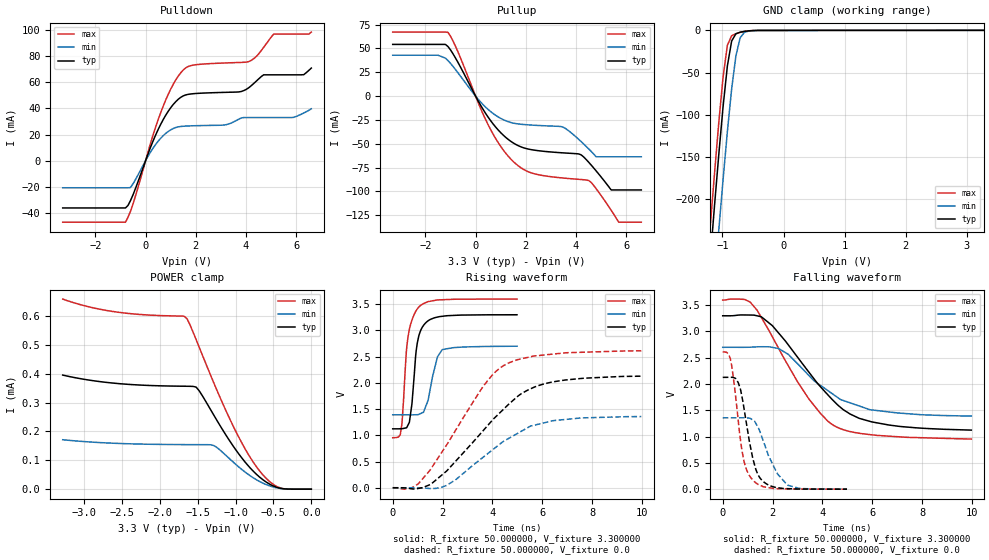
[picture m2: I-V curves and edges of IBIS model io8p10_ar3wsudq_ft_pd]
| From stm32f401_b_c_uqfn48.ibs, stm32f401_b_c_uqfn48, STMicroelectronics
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|   Model io8p10_ar3wsudq_ft_pd
[Model]  io8p10_ar3wsudq_ft_pd
Model_type I/O
Polarity   Non-Inverting
Enable   Active-Low
Vinl =   0.990000V
Vinh =   2.310000V
Vmeas =  1.650000V
Cref =   40.000000pF
Rref =   100.000000M
Vref =   0.0V
C_comp   3.843100pF   3.761700pF   3.937000pF
[Temperature Range]   25.000000   0.125000k   -40.000000
[Pullup Reference]   3.300000V   2.700000V   3.600000V
[Pulldown Reference]   0.0V   0.0V   0.0V
[POWER Clamp Reference]   3.300000V   2.700000V   3.600000V
[GND Clamp Reference]   0.0V   0.0V   0.0V
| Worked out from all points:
|   slope of the pulldown table from 0 to 0.495 V, typ, clamps not added: 20.9 ohm
|   slope of the pullup table from 0 to 0.495 V, typ, clamps not added: 22.6 ohm
|   GND clamp passes 1 mA (typ) near -0.62 V on its own axis
|   rising waveform, R_fixture 50.000000, V_fixture 3.300000: 20-80 % time 273ps typ, 357ps min, 284ps max; typ from 1.12 V to 3.3 V
|   rising waveform, R_fixture 50.000000, V_fixture 0.0: 20-80 % time 2.54ns typ, 2.37ns min, 2.13ns max; typ from 0 V to 2.13 V
|   falling waveform, R_fixture 50.000000, V_fixture 3.300000: 20-80 % time 2.29ns typ, 2.15ns min, 2.06ns max; typ from 3.3 V to 1.12 V
|   falling waveform, R_fixture 50.000000, V_fixture 0.0: 20-80 % time 504ps typ, 735ps min, 424ps max; typ from 2.13 V to 0 V
[Pulldown]
|Voltage   I(typ)   I(min)   I(max)
-3.3V     -36.18mA   -20.77mA   -47.07mA
-800mV    -36.18mA   -20.77mA   -47.07mA
-600mV    -30.5mA    -20.52mA   -38.69mA
700mV     31.4mA     19.11mA    41.71mA
1.2V      45.15mA    25.37mA    61.75mA
1.6V      50.35mA    26.5mA     71.06mA
3.1V      52.27mA    27.26mA    74.75mA
4.1V      55.7mA     33.01mA    75.8mA
4.7V      65.73mA    33.01mA    86.69mA
5.1V      65.73mA    33.01mA    96.89mA
6.3V      65.85mA    36.49mA    96.89mA
6.6V      70.9mA     39.7mA     98.44mA
[Pullup]
|Voltage   I(typ)   I(min)   I(max)
-3.3V     54.22mA    42.91mA    67.15mA
-1.1V     51.98mA    37.3mA     66.87mA
500mV     -22.07mA   -14mA      -30.03mA
1.5V      -49.1mA    -28.3mA    -68.56mA
2.2V      -56.04mA   -30.32mA   -80.35mA
3.5V      -59.53mA   -32.72mA   -85.92mA
4.2V      -61.52mA   -47.62mA   -87.46mA
4.5V      -69.21mA   -55.27mA   -88.44mA
4.8V      -78.37mA   -63.6mA    -97.02mA
5.4V      -98.4mA    -63.6mA    -119.7mA
5.7V      -98.4mA    -63.6mA    -132.2mA
6.6V      -98.4mA    -63.6mA    -132.2mA
[GND_clamp]
|Voltage   I(typ)   I(min)   I(max)
-3.3V     -2.325A    -2.404A    -2.299A
-1.2V     -270.2mA   -361.4mA   -232.1mA
-1.13V    -207.3mA   -298.1mA   -169mA
-1.06V    -146.7mA   -236.2mA   -108.8mA
-990mV    -90.18mA   -176.4mA   -54.97mA
-920mV    -42.21mA   -120mA     -17.69mA
-850mV    -12.58mA   -69.47mA   -6.279mA
-780mV    -3.983mA   -30.01mA   -3.9mA
-710mV    -2.112mA   -8.623mA   -2.396mA
-640mV    -1.159mA   -2.292mA   -1.234mA
-570mV    -535.1uA   -830.5uA   -490.2uA
3.28V     81.28uA    57.87uA    93.98uA
[POWER_clamp]
|Voltage   I(typ)   I(min)   I(max)
-3.28V    395.3uA    171.3uA    658.7uA
-2.6V     367.1uA    159uA      614.9uA
-1.68V    356.7uA    154.4uA    599.4uA
-1.64V    356.5uA    154.4uA    590.8uA
-1.52V    353.6uA    154.3uA    518.3uA
-1.48V    341.1uA    154.2uA    492.3uA
-1.28V    253.6uA    150.4uA    364.2uA
-960mV    123.1uA    77.56uA    181.6uA
-720mV    50.52uA    32.03uA    76.18uA
-560mV    18.94uA    12.27uA    28.65uA
-440mV    5.104uA    3.69uA     7.327uA
0V        0A         0A         0A
[Ramp]
| variable   typ   min   max
dV/dt_r  1.26618/2.54219n   0.81048/2.36713n   1.56348/2.13137n
dV/dt_f  1.28238/2.27117n   0.77610/2.13563n   1.57432/2.05496n
R_load = 50.000000
[Rising Waveform]
R_fixture= 50.000000
V_fixture= 3.300000
V_fixture_min= 2.700000
V_fixture_max= 3.600000
|time   V(typ)   V(min)   V(max)
0s        1.123V     1.391V     953.9mV
300.3ps   1.125V     1.391V     1.006V
370.4ps   1.126V     1.391V     1.218V
550.6ps   1.143V     1.391V     2.615V
670.7ps   1.254V     1.39V      3.025V
1.031ns   2.861V     1.396V     3.438V
1.411ns   3.181V     1.658V     3.547V
1.792ns   3.254V     2.491V     3.581V
1.982ns   3.269V     2.631V     3.585V
4.985ns   3.299V     2.699V     3.598V
[Rising Waveform]
R_fixture= 50.000000
V_fixture= 0.0
V_fixture_min= 0.0
V_fixture_max= 0.0
|time   V(typ)   V(min)   V(max)
0s        344.2uV    196.7uV    676.9uV
480.5ps   -2.556mV   137.5uV    -26.14mV
1.021ns   -13.38mV   -1.475mV   72.37mV
1.522ns   64.62mV    -15.8mV    352.4mV
2.142ns   310.8mV    41.11mV    803mV
3.644ns   1.098V     588.6mV    1.941V
4.484ns   1.516V     896.8mV    2.339V
5.165ns   1.796V     1.079V     2.459V
6.246ns   2V         1.258V     2.54V
9.97ns    2.127V     1.357V     2.611V
[Falling Waveform]
R_fixture= 50.000000
V_fixture= 3.300000
V_fixture_min= 2.700000
V_fixture_max= 3.600000
|time   V(typ)   V(min)   V(max)
0s        3.299V     2.699V     3.598V
1.101ns   3.312V     2.701V     3.559V
1.542ns   3.281V     2.709V     3.273V
2.242ns   2.97V      2.676V     2.678V
2.643ns   2.737V     2.559V     2.337V
3.463ns   2.222V     2.16V      1.71V
4.484ns   1.662V     1.786V     1.203V
5.105ns   1.431V     1.643V     1.096V
5.986ns   1.279V     1.507V     1.034V
9.97ns    1.123V     1.391V     953.9mV
[Falling Waveform]
R_fixture= 50.000000
V_fixture= 0.0
V_fixture_min= 0.0
V_fixture_max= 0.0
|time   V(typ)   V(min)   V(max)
0s        2.127V     1.357V     2.611V
300.3ps   2.128V     1.357V     2.49V
470.5ps   2.116V     1.357V     1.962V
620.6ps   2.029V     1.357V     1.317V
850.9ps   1.546V     1.359V     537.6mV
1.201ns   597.4mV    1.316V     177mV
1.622ns   147.8mV    925.3mV    48.44mV
2.192ns   28.84mV    293.7mV    9.852mV
2.593ns   10.2mV     79mV       5.363mV
4.985ns   344.2uV    196.7uV    676.9uV
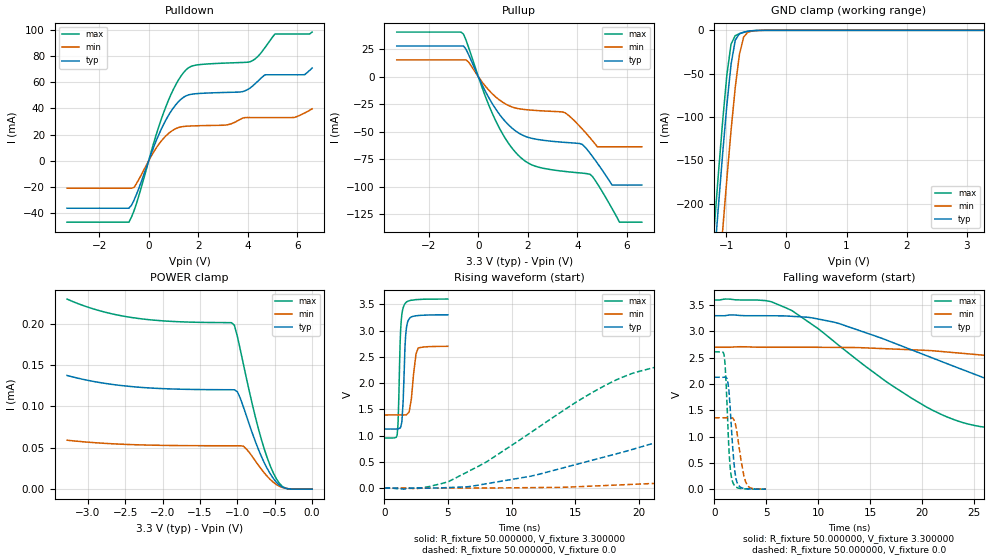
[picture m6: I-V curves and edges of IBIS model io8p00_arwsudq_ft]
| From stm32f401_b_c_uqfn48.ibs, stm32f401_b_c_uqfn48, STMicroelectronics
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|   Model io8p00_arwsudq_ft
[Model]  io8p00_arwsudq_ft
Model_type I/O
Polarity   Non-Inverting
Enable   Active-Low
Vinl =   0.990000V
Vinh =   2.310000V
Vmeas =  1.650000V
Cref =   50.000000pF
Rref =   100.000000M
Vref =   0.0V
C_comp   2.905500pF   2.831700pF   2.987900pF
[Temperature Range]   25.000000   0.125000k   -40.000000
[Pullup Reference]   3.300000V   2.700000V   3.600000V
[Pulldown Reference]   0.0V   0.0V   0.0V
[POWER Clamp Reference]   3.300000V   2.700000V   3.600000V
[GND Clamp Reference]   0.0V   0.0V   0.0V
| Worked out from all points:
|   slope of the pulldown table from 0 to 0.495 V, typ, clamps not added: 20.9 ohm
|   slope of the pullup table from 0 to 0.495 V, typ, clamps not added: 22.6 ohm
|   GND clamp passes 1 mA (typ) near -0.62 V on its own axis
|   rising waveform, R_fixture 50.000000, V_fixture 3.300000: 20-80 % time 211ps typ, 337ps min, 189ps max; typ from 1.12 V to 3.3 V
|   rising waveform, R_fixture 50.000000, V_fixture 0.0: 20-80 % time 19.7ns typ, 50.8ns min, 10.3ns max; typ from 0 V to 2.13 V
|   falling waveform, R_fixture 50.000000, V_fixture 3.300000: 20-80 % time 18.4ns typ, 38.3ns min, 11.3ns max; typ from 3.3 V to 1.12 V
|   falling waveform, R_fixture 50.000000, V_fixture 0.0: 20-80 % time 461ps typ, 654ps min, 370ps max; typ from 2.13 V to 0 V
[Pulldown]
|Voltage   I(typ)   I(min)   I(max)
-3.3V     -36.4mA    -21.08mA   -47.09mA
-800mV    -36.4mA    -21.08mA   -47.09mA
-600mV    -30.5mA    -20.54mA   -38.69mA
700mV     31.4mA     19.11mA    41.71mA
1.2V      45.15mA    25.37mA    61.75mA
1.6V      50.35mA    26.5mA     71.06mA
3.1V      52.28mA    27.26mA    74.76mA
4.1V      55.71mA    33.04mA    75.8mA
4.7V      65.81mA    33.04mA    86.69mA
5.1V      65.81mA    33.04mA    97.04mA
6.3V      65.87mA    36.5mA     97.04mA
6.6V      70.93mA    39.72mA    98.49mA
[Pullup]
|Voltage   I(typ)   I(min)   I(max)
-3.3V     28.03mA    15.43mA    40.68mA
-700mV    28.03mA    15.43mA    40.68mA
-400mV    20.31mA    13.47mA    26.93mA
600mV     -25.77mA   -16.23mA   -35.13mA
1.6V      -50.64mA   -28.81mA   -70.96mA
3.5V      -59.53mA   -32.65mA   -85.92mA
4.2V      -61.44mA   -47.49mA   -87.46mA
4.5V      -69.08mA   -55.13mA   -88.39mA
4.8V      -78.24mA   -63.5mA    -96.88mA
5.4V      -98.3mA    -63.5mA    -119.6mA
5.7V      -98.3mA    -63.5mA    -132mA
6.6V      -98.3mA    -63.5mA    -132mA
[GND_clamp]
|Voltage   I(typ)   I(min)   I(max)
-3.3V     -2.32A     -2.398A    -2.294A
-1.2V     -266mA     -356.2mA   -228.4mA
-1.13V    -203.2mA   -293mA     -165.3mA
-1.06V    -142.7mA   -231.3mA   -105.2mA
-990mV    -86.51mA   -171.7mA   -51.78mA
-920mV    -39.3mA    -115.7mA   -15.93mA
-850mV    -11.37mA   -65.76mA   -6.097mA
-780mV    -3.83mA    -27.55mA   -3.88mA
-710mV    -2.09mA    -7.747mA   -2.382mA
-640mV    -1.147mA   -2.129mA   -1.22mA
-570mV    -523.9uA   -800uA     -476.9uA
3.28V     0A         0A         0A
[POWER_clamp]
|Voltage   I(typ)   I(min)   I(max)
-3.28V    137.3uA    59.14uA    229.6uA
-2.36V    123.4uA    53.65uA    206.6uA
-1.08V    120.1uA    52.41uA    201.1uA
-1.04V    120uA      52.41uA    198uA
-1V       117.7uA    52.4uA     184.5uA
-920mV    99.46uA    51.91uA    151.2uA
-720mV    48.42uA    29.12uA    73.51uA
-600mV    24.82uA    15.47uA    37.72uA
-520mV    13.1uA     8.45uA     19.84uA
-440mV    5.058uA    3.61uA     7.276uA
-360mV    1.193uA    1.129uA    1.311uA
0V        0A         0A         0A
[Ramp]
| variable   typ   min   max
dV/dt_r  1.27746/19.70668n   0.81594/50.89464n   1.56731/10.31914n
dV/dt_f  1.30698/18.44695n   0.78480/38.43512n   1.58789/11.32160n
R_load = 50.000000
[Rising Waveform]
R_fixture= 50.000000
V_fixture= 3.300000
V_fixture_min= 2.700000
V_fixture_max= 3.600000
|time   V(typ)   V(min)   V(max)
0s        1.124V     1.392V     953.5mV
1.001ns   1.126V     1.392V     1.012V
1.071ns   1.127V     1.392V     1.26V
1.271ns   1.159V     1.392V     3.005V
1.371ns   1.27V      1.391V     3.312V
1.532ns   2.086V     1.392V     3.475V
1.672ns   2.92V      1.394V     3.53V
1.932ns   3.219V     1.445V     3.567V
2.653ns   3.286V     2.667V     3.591V
4.985ns   3.3V       2.7V       3.6V
[Rising Waveform]
R_fixture= 50.000000
V_fixture= 0.0
V_fixture_min= 0.0
V_fixture_max= 0.0
|time   V(typ)   V(min)   V(max)
0s        1.506uV    364.5nV    16.56uV
5.005ns   8.627mV    -160uV     117.5mV
19.52ns   735.6mV    69.76mV    2.185V
26.03ns   1.193V     138.3mV    2.462V
34.03ns   1.683V     279.6mV    2.558V
41.04ns   1.911V     403.2mV    2.582V
57.06ns   2.066V     700.6mV    2.607V
88.09ns   2.119V     1.131V     2.612V
115.1ns   2.128V     1.292V     2.612V
249.2ns   2.129V     1.359V     2.612V
[Falling Waveform]
R_fixture= 50.000000
V_fixture= 3.300000
V_fixture_min= 2.700000
V_fixture_max= 3.600000
|time   V(typ)   V(min)   V(max)
0s        3.3V       2.7V       3.6V
5.506ns   3.299V     2.7V       3.565V
11.51ns   3.178V     2.697V     2.814V
17.02ns   2.803V     2.668V     1.984V
22.02ns   2.418V     2.616V     1.407V
31.53ns   1.726V     2.437V     1.075V
46.05ns   1.281V     2.083V     999.4mV
65.07ns   1.179V     1.708V     968mV
86.59ns   1.146V     1.527V     956.5mV
249.2ns   1.124V     1.392V     953.5mV
[Falling Waveform]
R_fixture= 50.000000
V_fixture= 0.0
V_fixture_min= 0.0
V_fixture_max= 0.0
|time   V(typ)   V(min)   V(max)
0s        2.129V     1.359V     2.612V
981ps     2.13V      1.359V     2.514V
1.151ns   2.121V     1.358V     1.992V
1.311ns   2.034V     1.358V     1.244V
1.491ns   1.679V     1.36V      532mV
1.792ns   768.6mV    1.352V     130.2mV
2.182ns   139.1mV    1.095V     32.63mV
2.843ns   15.25mV    270mV      6.343mV
3.143ns   7.383mV    88.48mV    4.542mV
4.985ns   1.506uV    364.5nV    16.56uV
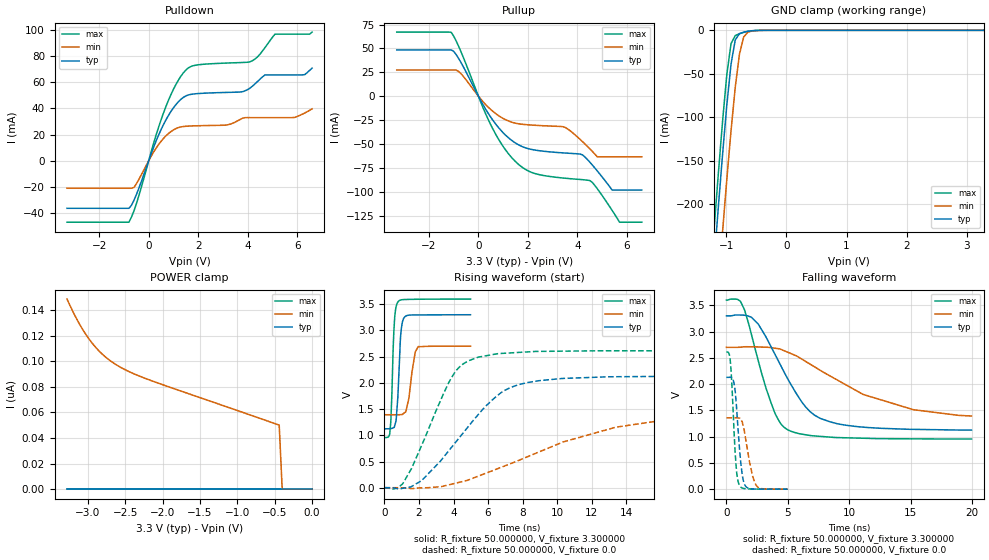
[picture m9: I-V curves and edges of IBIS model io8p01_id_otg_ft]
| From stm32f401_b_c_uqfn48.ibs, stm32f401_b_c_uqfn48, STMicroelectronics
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|   Model io8p01_id_otg_ft
[Model]  io8p01_id_otg_ft
Model_type I/O
Polarity   Non-Inverting
Enable   Active-Low
Vinl =   0.990000V
Vinh =   2.310000V
Vmeas =  1.650000V
Cref =   50.000000pF
Rref =   100.000000M
Vref =   0.0V
C_comp   2.283100pF   2.214500pF   2.357400pF
[Temperature Range]   25.000000   0.125000k   -40.000000
[Pullup Reference]   3.300000V   2.700000V   3.600000V
[Pulldown Reference]   0.0V   0.0V   0.0V
[POWER Clamp Reference]   3.300000V   2.700000V   3.600000V
[GND Clamp Reference]   0.0V   0.0V   0.0V
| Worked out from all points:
|   slope of the pulldown table from 0 to 0.495 V, typ, clamps not added: 20.9 ohm
|   slope of the pullup table from 0 to 0.495 V, typ, clamps not added: 22.6 ohm
|   GND clamp passes 1 mA (typ) near -0.62 V on its own axis
|   rising waveform, R_fixture 50.000000, V_fixture 3.300000: 20-80 % time 192ps typ, 331ps min, 165ps max; typ from 1.12 V to 3.3 V
|   rising waveform, R_fixture 50.000000, V_fixture 0.0: 20-80 % time 3.34ns typ, 6.83ns min, 2.09ns max; typ from 0 V to 2.13 V
|   falling waveform, R_fixture 50.000000, V_fixture 3.300000: 20-80 % time 3.18ns typ, 6.84ns min, 1.99ns max; typ from 3.3 V to 1.12 V
|   falling waveform, R_fixture 50.000000, V_fixture 0.0: 20-80 % time 434ps typ, 634ps min, 342ps max; typ from 2.13 V to 0 V
[Pulldown]
|Voltage   I(typ)   I(min)   I(max)
-3.3V     -36.46mA   -21.09mA   -47.09mA
-800mV    -36.46mA   -21.09mA   -47.09mA
-600mV    -30.5mA    -20.54mA   -38.68mA
700mV     31.4mA     19.11mA    41.71mA
1.2V      45.15mA    25.37mA    61.75mA
1.6V      50.35mA    26.5mA     71.06mA
3.1V      52.28mA    27.26mA    74.76mA
4.1V      55.71mA    33mA       75.81mA
4.7V      65.72mA    33mA       86.7mA
5.1V      65.72mA    33mA       96.91mA
6.3V      65.88mA    36.51mA    96.91mA
6.6V      70.94mA    39.72mA    98.51mA
[Pullup]
|Voltage   I(typ)   I(min)   I(max)
-3.3V     48.55mA    27.44mA    67.19mA
-1.1V     48.55mA    27.44mA    66.9mA
-700mV    35.14mA    23.48mA    46.36mA
500mV     -22.07mA   -14mA      -30.03mA
1.5V      -49.1mA    -28.3mA    -68.56mA
2.2V      -56.05mA   -30.32mA   -80.35mA
3.5V      -59.53mA   -32.65mA   -85.92mA
4.5V      -69.06mA   -55.12mA   -88.38mA
4.8V      -78.22mA   -63.5mA    -96.84mA
5.4V      -98.3mA    -63.5mA    -119.6mA
5.7V      -98.3mA    -63.5mA    -132mA
6.6V      -98.3mA    -63.5mA    -132mA
[GND_clamp]
|Voltage   I(typ)   I(min)   I(max)
-3.3V     -2.318A    -2.397A    -2.291A
-1.2V     -265.5mA   -356.1mA   -227.2mA
-1.13V    -202.7mA   -292.9mA   -164.1mA
-1.06V    -142.2mA   -231.2mA   -104.1mA
-990mV    -85.98mA   -171.6mA   -50.73mA
-920mV    -38.81mA   -115.5mA   -15.3mA
-850mV    -11.1mA    -65.61mA   -6.021mA
-780mV    -3.796mA   -27.43mA   -3.892mA
-710mV    -2.096mA   -7.699mA   -2.393mA
-640mV    -1.154mA   -2.125mA   -1.227mA
-570mV    -528.1uA   -803.6uA   -480.7uA
3.28V     0A         0A         0A
[POWER_clamp]
|Voltage   I(typ)   I(min)   I(max)
-3.28V    0A         148.5nA    0A
-3.2V     0A         138.6nA    0A
-3.12V    0A         129.7nA    0A
-3.04V    0A         122nA      0A
-2.96V    0A         115.3nA    0A
-2.8V     0A         105.1nA    0A
-2.6V     0A         96.44nA    0A
-2.4V     0A         90.52nA    0A
-2.16V    0A         84.97nA    0A
-440mV    0A         50.04nA    0A
-400mV    0A         0A         0A
0V        0A         0A         0A
[Ramp]
| variable   typ   min   max
dV/dt_r  1.27758/3.33724n   0.79926/6.83450n   1.56726/2.08840n
dV/dt_f  1.30236/3.17443n   0.74064/6.80123n   1.58786/1.98906n
R_load = 50.000000
[Rising Waveform]
R_fixture= 50.000000
V_fixture= 3.300000
V_fixture_min= 2.700000
V_fixture_max= 3.600000
|time   V(typ)   V(min)   V(max)
0s        1.124V     1.392V     954.3mV
300.3ps   1.126V     1.392V     1.015V
370.4ps   1.128V     1.392V     1.28V
500.5ps   1.142V     1.392V     2.635V
590.6ps   1.182V     1.392V     3.246V
760.8ps   1.665V     1.391V     3.534V
940.9ps   2.917V     1.394V     3.582V
1.161ns   3.255V     1.431V     3.59V
1.952ns   3.296V     2.691V     3.595V
4.985ns   3.3V       2.7V       3.599V
[Rising Waveform]
R_fixture= 50.000000
V_fixture= 0.0
V_fixture_min= 0.0
V_fixture_max= 0.0
|time   V(typ)   V(min)   V(max)
0s        358.2uV    205.3uV    684.7uV
1.081ns   -9.554mV   -1.989mV   89.21mV
2.162ns   138.2mV    -2.126mV   814.9mV
3.724ns   704.7mV    54.71mV    2.005V
4.244ns   917.5mV    95.9mV     2.269V
4.885ns   1.178V     150.7mV    2.423V
6.767ns   1.817V     390.3mV    2.562V
8.248ns   2.003V     586mV      2.59V
13.41ns   2.117V     1.155V     2.612V
19.94ns   2.129V     1.359V     2.612V
[Falling Waveform]
R_fixture= 50.000000
V_fixture= 3.300000
V_fixture_min= 2.700000
V_fixture_max= 3.600000
|time   V(typ)   V(min)   V(max)
0s        3.3V       2.7V       3.599V
920.9ps   3.315V     2.7V       3.611V
1.441ns   3.311V     2.71V      3.43V
2.563ns   3.149V     2.707V     2.469V
3.644ns   2.705V     2.693V     1.635V
4.965ns   2.11V      2.609V     1.134V
6.807ns   1.475V     2.38V      1.022V
8.408ns   1.284V     2.158V     991.3mV
15.22ns   1.139V     1.513V     958.1mV
19.94ns   1.124V     1.392V     954.3mV
[Falling Waveform]
R_fixture= 50.000000
V_fixture= 0.0
V_fixture_min= 0.0
V_fixture_max= 0.0
|time   V(typ)   V(min)   V(max)
0s        2.129V     1.359V     2.612V
300.3ps   2.13V      1.359V     2.474V
460.5ps   2.118V     1.358V     1.91V
620.6ps   2.016V     1.358V     1.086V
830.8ps   1.524V     1.36V      324.7mV
1.041ns   833.4mV    1.353V     83.01mV
1.451ns   103.7mV    1.118V     11.68mV
1.872ns   12.72mV    525.3mV    4.407mV
2.422ns   2.904mV    73.74mV    2.293mV
4.985ns   358.2uV    205.3uV    684.7uV
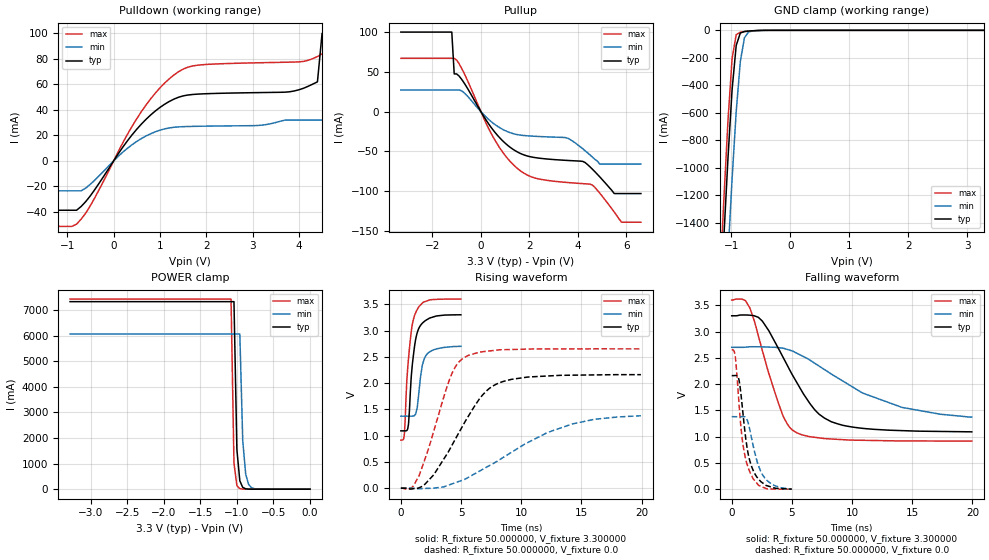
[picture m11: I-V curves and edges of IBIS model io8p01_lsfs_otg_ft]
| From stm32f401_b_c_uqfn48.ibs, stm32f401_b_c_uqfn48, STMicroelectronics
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|   Model io8p01_lsfs_otg_ft
[Model]  io8p01_lsfs_otg_ft
Model_type I/O
Polarity   Non-Inverting
Enable   Active-Low
Vinl =   0.990000V
Vinh =   2.310000V
Vmeas =  1.650000V
Cref =   50.000000pF
Rref =   100.000000M
Vref =   0.0V
C_comp   8.196500pF   7.968500pF   8.492600pF
[Temperature Range]   25.000000   0.125000k   -40.000000
[Pullup Reference]   3.300000V   2.700000V   3.600000V
[Pulldown Reference]   0.0V   0.0V   0.0V
[POWER Clamp Reference]   3.300000V   2.700000V   3.600000V
[GND Clamp Reference]   0.0V   0.0V   0.0V
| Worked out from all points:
|   slope of the pulldown table from 0 to 0.495 V, typ, clamps not added: 20.1 ohm
|   slope of the pullup table from 0 to 0.495 V, typ, clamps not added: 21.8 ohm
|   GND clamp passes 1 mA (typ) near -0.52 V on its own axis
|   POWER clamp passes 1 mA (typ) near -0.81 V on its own axis
|   rising waveform, R_fixture 50.000000, V_fixture 3.300000: 20-80 % time 528ps typ, 494ps min, 531ps max; typ from 1.09 V to 3.3 V
|   rising waveform, R_fixture 50.000000, V_fixture 0.0: 20-80 % time 3.4ns typ, 6.58ns min, 2.17ns max; typ from 0 V to 2.16 V
|   falling waveform, R_fixture 50.000000, V_fixture 3.300000: 20-80 % time 3.37ns typ, 6.54ns min, 2.12ns max; typ from 3.3 V to 1.09 V
|   falling waveform, R_fixture 50.000000, V_fixture 0.0: 20-80 % time 848ps typ, 1.03ns min, 757ps max; typ from 2.16 V to 0 V
[Pulldown]
|Voltage   I(typ)   I(min)   I(max)
-3.3V     -38.65mA   -23.43mA   -51.3mA
-800mV    -38.65mA   -23.43mA   -49.55mA
600mV     28.89mA    17.56mA    38.66mA
1.4V      49.88mA    26.66mA    69.85mA
4.1V      56.96mA    32mA       77.99mA
4.4V      62mA       32mA       81.81mA
4.5V      100mA      32mA       83.91mA
4.7V      100mA      32mA       89mA
4.8V      100mA      32mA       100mA
5.1V      100mA      32mA       100mA
5.2V      1A         1A         100mA
6.6V      1A         1A         1A
[Pullup]
|Voltage   I(typ)   I(min)   I(max)
-3.3V     100mA      27.2mA     67mA
-1.2V     100mA      27.2mA     67mA
-1.1V     47.4mA     27.2mA     67mA
-700mV    36.47mA    23.93mA    48.81mA
500mV     -22.94mA   -14.36mA   -31.63mA
1.3V      -46.85mA   -27.39mA   -65.63mA
2.1V      -57.1mA    -30.77mA   -82.2mA
3.5V      -61.24mA   -32.7mA    -88.93mA
4.6V      -72.4mA    -57.1mA    -92.27mA
5.5V      -103mA     -66mA      -126.3mA
5.8V      -103mA     -66mA      -139mA
6.6V      -103mA     -66mA      -139mA
[GND_clamp]
|Voltage   I(typ)   I(min)   I(max)
-3.3V     -9.479A    -9.465A    -9.974A
-1.2V     -2.125A    -2.854A    -1.857A
-1.13V    -1.511A    -2.236A    -1.236A
-1.06V    -933.3mA   -1.641A    -660.9mA
-990mV    -433.3mA   -1.082A    -206.9mA
-920mV    -110.3mA   -591mA     -31.45mA
-850mV    -19.78mA   -226.7mA   -13.65mA
-780mV    -8.311mA   -53.93mA   -9.506mA
-710mV    -5.285mA   -11.94mA   -6.262mA
-640mV    -3.232mA   -4.282mA   -3.577mA
3.28V     0A         0A         0A
[POWER_clamp]
|Voltage   I(typ)   I(min)   I(max)
-3.28V    7.328A     6.064A     7.43A
-1.08V    7.328A     6.064A     7.43A
-1.04V    7.328A     6.064A     1.015A
-1V       1.545A     6.064A     138.6mA
-960mV    325.6mA    6.064A     18.93mA
-920mV    68.64mA    1.89A      2.585mA
-880mV    14.47mA    589mA      353uA
-840mV    3.05mA     183.6mA    105.2uA
-800mV    642.9uA    57.21mA    105.2uA
-720mV    28.59uA    5.557mA    105.2uA
0V        0A         0A         0A
[Ramp]
| variable   typ   min   max
dV/dt_r  1.29659/3.39767n   0.80808/6.55318n   1.59073/2.17075n
dV/dt_f  1.32168/3.36534n   0.74892/6.48776n   1.61143/2.12165n
R_load = 50.000000
[Rising Waveform]
R_fixture= 50.000000
V_fixture= 3.300000
V_fixture_min= 2.700000
V_fixture_max= 3.600000
|time   V(typ)   V(min)   V(max)
0s        1.091V     1.371V     914.3mV
290.3ps   1.091V     1.371V     1.025V
500.5ps   1.099V     1.371V     2.067V
630.6ps   1.212V     1.37V      2.457V
870.9ps   2.145V     1.37V      2.993V
1.191ns   2.782V     1.401V     3.318V
1.361ns   2.961V     1.536V     3.4V
1.782ns   3.139V     2.337V     3.522V
2.082ns   3.196V     2.523V     3.558V
4.985ns   3.3V       2.7V       3.6V
[Rising Waveform]
R_fixture= 50.000000
V_fixture= 0.0
V_fixture_min= 0.0
V_fixture_max= 0.0
|time   V(typ)   V(min)   V(max)
0s        34.46uV    22.65uV    108.4uV
800.8ps   -16.48mV   73.79uV    -1.256mV
1.522ns   8.561mV    -12.54mV   241.4mV
2.723ns   252.5mV    385.3uV    1.079V
4.204ns   799.8mV    77.68mV    2.16V
5.526ns   1.339V     196.5mV    2.52V
7.287ns   1.887V     421mV      2.61V
9.169ns   2.071V     679.8mV    2.639V
14.25ns   2.151V     1.223V     2.651V
19.94ns   2.161V     1.379V     2.652V
[Falling Waveform]
R_fixture= 50.000000
V_fixture= 3.300000
V_fixture_min= 2.700000
V_fixture_max= 3.600000
|time   V(typ)   V(min)   V(max)
0s        3.3V       2.7V       3.6V
880.9ps   3.315V     2.7V       3.615V
1.481ns   3.311V     2.71V      3.46V
2.563ns   3.193V     2.708V     2.625V
4.204ns   2.538V     2.685V     1.43V
5.285ns   2.078V     2.603V     1.088V
7.247ns   1.428V     2.344V     976.5mV
8.849ns   1.24V      2.111V     947.2mV
14.13ns   1.114V     1.557V     919mV
19.94ns   1.091V     1.371V     914.3mV
[Falling Waveform]
R_fixture= 50.000000
V_fixture= 0.0
V_fixture_min= 0.0
V_fixture_max= 0.0
|time   V(typ)   V(min)   V(max)
0s        2.161V     1.379V     2.652V
280.3ps   2.162V     1.379V     2.551V
610.6ps   2.074V     1.379V     1.619V
760.8ps   1.826V     1.38V      1.187V
981ps     1.343V     1.381V     783.8mV
1.461ns   577.3mV    1.177V     353.2mV
1.892ns   306.5mV    714.6mV    168mV
2.472ns   134.6mV    303.3mV    48.93mV
3.363ns   35.9mV     86.73mV    3.313mV
4.985ns   34.46uV    22.65uV    108.4uV
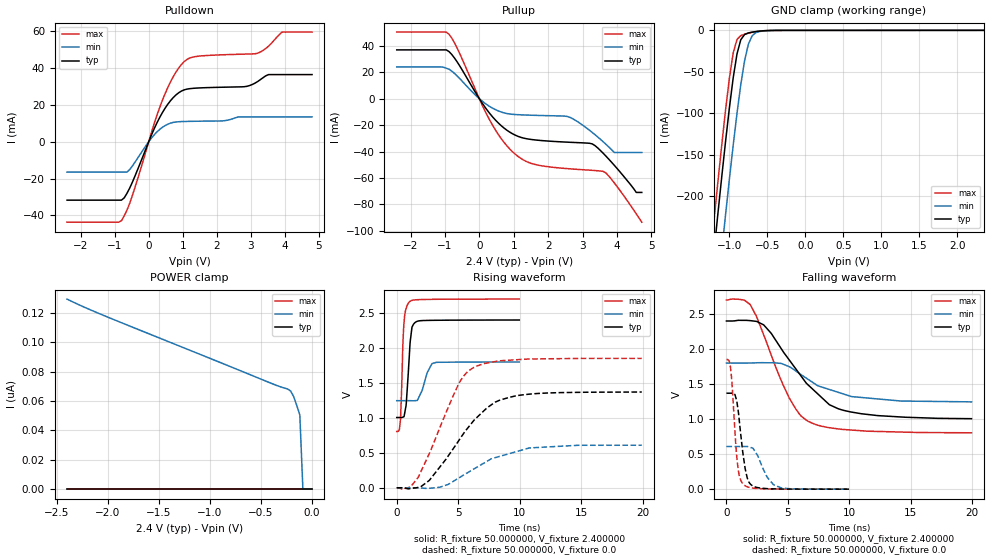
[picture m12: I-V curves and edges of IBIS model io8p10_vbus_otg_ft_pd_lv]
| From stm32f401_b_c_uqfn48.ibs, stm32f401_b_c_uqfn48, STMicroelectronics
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|   Model io8p10_vbus_otg_ft_pd_lv
[Model]  io8p10_vbus_otg_ft_pd_lv
Model_type I/O
Polarity   Non-Inverting
Enable   Active-Low
Vinl =   0.720000V
Vinh =   1.680000V
Vmeas =  1.200000V
Cref =   40.000000pF
Rref =   100.000000M
Vref =   0.0V
C_comp   3.193600pF   3.100000pF   3.332100pF
[Temperature Range]   25.000000   0.125000k   -40.000000
[Pullup Reference]   2.400000V   1.800000V   2.700000V
[Pulldown Reference]   0.0V   0.0V   0.0V
[POWER Clamp Reference]   2.400000V   1.800000V   2.700000V
[GND Clamp Reference]   0.0V   0.0V   0.0V
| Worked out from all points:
|   slope of the pulldown table from 0 to 0.36 V, typ, clamps not added: 25 ohm
|   slope of the pullup table from 0 to 0.36 V, typ, clamps not added: 27.7 ohm
|   GND clamp passes 1 mA (typ) near -0.61 V on its own axis
|   rising waveform, R_fixture 50.000000, V_fixture 2.400000: 20-80 % time 311ps typ, 635ps min, 224ps max; typ from 1 V to 2.4 V
|   rising waveform, R_fixture 50.000000, V_fixture 0.0: 20-80 % time 3.66ns typ, 4.25ns min, 2.69ns max; typ from 0 V to 1.37 V
|   falling waveform, R_fixture 50.000000, V_fixture 2.400000: 20-80 % time 3.86ns typ, 3.93ns min, 2.74ns max; typ from 2.4 V to 1 V
|   falling waveform, R_fixture 50.000000, V_fixture 0.0: 20-80 % time 572ps typ, 1.04ns min, 434ps max; typ from 1.37 V to 0 V
[Pulldown]
|Voltage   I(typ)   I(min)   I(max)
-2.4V     -31.69mA   -16.5mA    -43.66mA
-800mV    -31.69mA   -16.5mA    -42.82mA
-480mV    -21.96mA   -13.17mA   -29.19mA
80mV      3.63mA     1.966mA    5.014mA
480mV     18.15mA    8.738mA    26.02mA
800mV     25.38mA    10.72mA    37.77mA
1.12V     28.53mA    11.02mA    44.6mA
2.8V      29.84mA    13.49mA    47.53mA
3.2V      32.65mA    13.49mA    48.04mA
3.52V     36.42mA    13.49mA    51.83mA
3.92V     36.42mA    13.49mA    59.49mA
4.8V      36.42mA    13.49mA    59.49mA
[Pullup]
|Voltage   I(typ)   I(min)   I(max)
-2.4V     36.91mA    24.03mA    50.37mA
-960mV    36.91mA    23.05mA    50.37mA
-640mV    27.65mA    17.03mA    37.99mA
320mV     -11.75mA   -6.207mA   -17.08mA
960mV     -26.47mA   -11.82mA   -40.02mA
1.52V     -30.88mA   -12.51mA   -49.05mA
2.56V     -32.88mA   -13.49mA   -52.9mA
3.28V     -34.19mA   -25.52mA   -54.18mA
3.6V      -41.31mA   -32.61mA   -54.99mA
3.92V     -50.33mA   -40.7mA    -63.62mA
4.56V     -70.9mA    -40.7mA    -87.08mA
4.72V     -70.9mA    -40.7mA    -93.4mA
[GND_clamp]
|Voltage   I(typ)   I(min)   I(max)
-2.4V     -1.424A    -1.508A    -1.393A
-1.25V    -311.3mA   -401.9mA   -273.4mA
-1.2V     -265.5mA   -356.1mA   -227.3mA
-1.15V    -220.5mA   -310.9mA   -182mA
-1.1V     -176.4mA   -266.2mA   -138mA
-1.05V    -133.9mA   -222.5mA   -96.06mA
-950mV    -57.51mA   -139mA     -27.36mA
-900mV    -28.55mA   -100.5mA   -11.04mA
-850mV    -11.34mA   -65.68mA   -6.337mA
-750mV    -3.08mA    -16.7mA    -3.439mA
-600mV    -875.9uA   -1.303mA   -865.8uA
2.35V     58.09uA    37.92uA    67.25uA
[POWER_clamp]
|Voltage   I(typ)   I(min)   I(max)
-2.4V     0A         129.4nA    0A
-1.98V    0A         116.5nA    0A
-390mV    0A         71.78nA    0A
-240mV    0A         68.22nA    0A
-210mV    0A         66.81nA    0A
-180mV    0A         62.95nA    0A
-120mV    0A         50.47nA    0A
-90mV     0A         0A         0A
0V        0A         0A         0A
[Ramp]
| variable   typ   min   max
dV/dt_r  0.82140/3.65237n   0.36512/4.25101n   1.11042/2.68682n
dV/dt_f  0.83286/3.85867n   0.33324/3.96826n   1.13636/2.74525n
R_load = 50.000000
[Rising Waveform]
R_fixture= 50.000000
V_fixture= 2.400000
V_fixture_min= 1.800000
V_fixture_max= 2.700000
|time   V(typ)   V(min)   V(max)
0s        1.005V     1.245V     804.2mV
300.3ps   1.005V     1.245V     972.5mV
520.5ps   1.011V     1.246V     2.144V
600.6ps   1.023V     1.246V     2.377V
760.8ps   1.177V     1.246V     2.564V
1.001ns   1.823V     1.245V     2.654V
1.241ns   2.297V     1.245V     2.679V
1.662ns   2.38V      1.248V     2.689V
2.883ns   2.394V     1.777V     2.694V
9.97ns    2.399V     1.799V     2.698V
[Rising Waveform]
R_fixture= 50.000000
V_fixture= 0.0
V_fixture_min= 0.0
V_fixture_max= 0.0
|time   V(typ)   V(min)   V(max)
0s        170.1uV    66.6uV     528uV
1.121ns   -11.63mV   128.9uV    13.3mV
1.762ns   6.416mV    -1.762mV   154.5mV
2.643ns   104.3mV    -6.978mV   486.8mV
5.045ns   674.3mV    139.6mV    1.489V
6.246ns   956.7mV    265.5mV    1.718V
8.008ns   1.224V     430.5mV    1.805V
9.73ns    1.316V     516.7mV    1.831V
14.77ns   1.365V     607.6mV    1.849V
19.94ns   1.369V     608.4mV    1.85V
[Falling Waveform]
R_fixture= 50.000000
V_fixture= 2.400000
V_fixture_min= 1.800000
V_fixture_max= 2.700000
|time   V(typ)   V(min)   V(max)
0s        2.399V     1.799V     2.698V
1.441ns   2.408V     1.799V     2.696V
1.922ns   2.404V     1.8V       2.636V
3.043ns   2.341V     1.804V     2.195V
5.085ns   1.849V     1.749V     1.31V
5.966ns   1.639V     1.646V     1.064V
6.647ns   1.487V     1.566V     968.7mV
8.368ns   1.206V     1.423V     876.9mV
10.05ns   1.104V     1.328V     844.8mV
19.94ns   1.005V     1.245V     804.2mV
[Falling Waveform]
R_fixture= 50.000000
V_fixture= 0.0
V_fixture_min= 0.0
V_fixture_max= 0.0
|time   V(typ)   V(min)   V(max)
0s        1.369V     608.4mV    1.85V
340.3ps   1.369V     608.4mV    1.724V
840.8ps   1.258V     608.2mV    462.2mV
1.061ns   950.6mV    607.9mV    182.6mV
1.381ns   463.1mV    608.2mV    68.25mV
1.702ns   155.1mV    608.7mV    33.81mV
2.302ns   33.07mV    544.6mV    12.14mV
3.323ns   7.172mV    168.1mV    3.242mV
4.464ns   2.014mV    17.56mV    1.494mV
9.97ns    170.1uV    66.6uV     528uV
